VERSION 5.7 ;
  NOWIREEXTENSIONATPIN ON ;
  DIVIDERCHAR "/" ;
  BUSBITCHARS "[]" ;
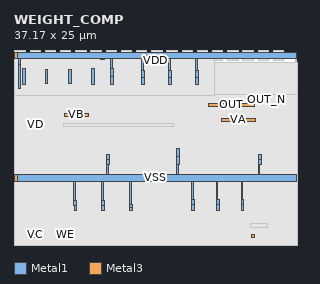
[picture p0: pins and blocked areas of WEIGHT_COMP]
MACRO WEIGHT_COMP
  CLASS BLOCK ;
  FOREIGN WEIGHT_COMP ;
  ORIGIN 1.450 4.210 ;
  SIZE 37.170 BY 25.000 ;
  PIN VSS
    DIRECTION INOUT ;
    USE GROUND ;
    PORT
      LAYER Metal1 ;
        RECT 10.760 6.660 11.120 7.280 ;
        RECT 19.980 7.040 20.340 8.040 ;
        RECT 10.730 6.040 11.120 6.660 ;
        RECT 19.950 6.040 20.340 7.040 ;
        RECT 30.700 6.660 31.060 7.280 ;
        RECT 30.670 6.040 31.060 6.660 ;
        RECT 10.730 4.710 10.960 6.040 ;
        RECT 19.950 4.710 20.180 6.040 ;
        RECT 30.670 4.710 30.900 6.040 ;
        RECT -1.000 3.810 35.720 4.710 ;
        RECT 6.420 1.240 6.650 3.810 ;
        RECT 10.080 1.240 10.310 3.810 ;
        RECT 6.420 0.620 6.810 1.240 ;
        RECT 10.080 0.620 10.470 1.240 ;
        RECT 6.450 0.000 6.810 0.620 ;
        RECT 10.110 0.000 10.470 0.620 ;
        RECT 13.740 0.700 13.970 3.810 ;
        RECT 21.900 1.320 22.130 3.810 ;
        RECT 25.160 1.320 25.390 3.810 ;
        RECT 28.420 1.320 28.650 3.810 ;
        RECT 13.740 0.350 14.130 0.700 ;
        RECT 21.900 0.660 22.290 1.320 ;
        RECT 25.160 0.660 25.550 1.320 ;
        RECT 28.420 0.660 28.810 1.320 ;
        RECT 13.770 0.000 14.130 0.350 ;
        RECT 21.930 0.000 22.290 0.660 ;
        RECT 25.190 0.000 25.550 0.660 ;
        RECT 28.450 0.000 28.810 0.660 ;
      LAYER Metal3 ;
        RECT -1.450 3.810 35.720 4.710 ;
    END
  END VSS
  PIN VDD
    DIRECTION INOUT ;
    USE POWER ;
    PORT
      LAYER Metal1 ;
        RECT -1.000 19.890 35.720 20.790 ;
        RECT -0.865 19.140 -0.635 19.890 ;
        RECT 9.960 19.790 10.440 19.890 ;
        RECT -0.900 15.980 -0.600 19.140 ;
        RECT 11.280 18.560 11.510 19.890 ;
        RECT -0.350 16.560 0.010 18.560 ;
        RECT 2.710 16.580 3.010 18.540 ;
        RECT 5.750 16.580 6.050 18.540 ;
        RECT 8.750 16.560 9.110 18.560 ;
        RECT 11.280 17.560 11.670 18.560 ;
        RECT 11.310 16.560 11.670 17.560 ;
        RECT 15.340 18.390 15.570 19.890 ;
        RECT 17.580 19.790 18.060 19.890 ;
        RECT 18.900 18.390 19.130 19.890 ;
        RECT 22.460 18.390 22.690 19.890 ;
        RECT 15.340 17.475 15.730 18.390 ;
        RECT 18.900 17.475 19.290 18.390 ;
        RECT 22.460 17.475 22.850 18.390 ;
        RECT 15.370 16.560 15.730 17.475 ;
        RECT 18.930 16.560 19.290 17.475 ;
        RECT 22.490 16.560 22.850 17.475 ;
      LAYER Metal3 ;
        RECT -1.450 19.890 35.720 20.790 ;
    END
  END VDD
  PIN VD
    DIRECTION INPUT ;
    ANTENNAGATEAREA 4.960000 ;
    PORT
      LAYER Metal3 ;
      RECT 1.200 11.020 1.600 11.420 ;
    END
  END VD
  PIN WE
    DIRECTION INOUT ;
    ANTENNAGATEAREA 21.706999 ;
    ANTENNADIFFAREA 9.318399 ;
    PORT
      LAYER Metal3 ;
      RECT 5.120 -3.560 5.520 -3.160 ;
    END
  END WE
  PIN VA
    DIRECTION INPUT ;
    ANTENNAGATEAREA 4.960000 ;
    PORT
      LAYER Metal3 ;
      RECT 25.830 11.680 30.330 12.080 ;
    END
  END VA
  PIN VB
    DIRECTION INPUT ;
    ANTENNAGATEAREA 4.960000 ;
    PORT
      LAYER Metal3 ;
      RECT 5.190 12.340 8.290 12.740 ;
    END
  END VB
  PIN OUT
    DIRECTION INOUT ;
    ANTENNAGATEAREA 1.707000 ;
    ANTENNADIFFAREA 1.386000 ;
    PORT
      LAYER Metal3 ;
      RECT 24.105 13.660 30.165 14.060 ;
      RECT 29.765 -3.560 30.165 -3.160 ;
    END
  END OUT
  PIN OUT_N
    DIRECTION INOUT ;
    ANTENNADIFFAREA 1.386000 ;
    PORT
      LAYER Metal3 ;
      RECT 31.565 14.320 31.965 14.720 ;
    END
  END OUT_N
  PIN VC
    DIRECTION INPUT ;
    ANTENNAGATEAREA 4.960000 ;
    PORT
      LAYER Metal3 ;
      RECT 1.200 -3.560 1.600 -3.160 ;
    END
  END VC
  OBS
      LAYER Via1 ;
        RECT 13.970 0.690 15.430 1.510 ;
        RECT 15.470 0.690 16.930 1.510 ;
        RECT 16.970 0.690 18.430 1.510 ;
        RECT -1.340 3.570 0.040 4.950 ;
        RECT 0.660 3.570 2.040 4.950 ;
        RECT 2.660 3.570 4.040 4.950 ;
        RECT 4.660 3.570 6.040 4.950 ;
        RECT 6.660 3.570 8.040 4.950 ;
        RECT 12.660 3.570 14.040 4.950 ;
        RECT 14.660 3.570 16.040 4.950 ;
        RECT 16.660 3.570 18.040 4.950 ;
        RECT 18.660 3.570 20.040 4.950 ;
        RECT 24.660 3.570 26.040 4.950 ;
        RECT 26.660 3.570 28.040 4.950 ;
        RECT -1.440 -4.700 35.875 19.370 ;
        RECT -1.340 19.650 0.040 21.030 ;
        RECT 0.660 19.650 2.040 21.030 ;
        RECT 2.660 19.650 4.040 21.030 ;
        RECT 4.660 19.650 6.040 21.030 ;
        RECT 6.660 19.650 8.040 21.030 ;
        RECT 8.660 19.650 10.040 21.030 ;
        RECT 10.660 19.650 12.040 21.030 ;
        RECT 12.660 19.650 14.040 21.030 ;
        RECT 14.660 19.650 16.040 21.030 ;
        RECT 16.660 19.650 18.040 21.030 ;
        RECT 18.660 19.650 20.040 21.030 ;
        RECT 20.660 19.650 22.040 21.030 ;
        RECT 22.660 19.650 24.040 21.030 ;
        RECT 24.660 19.650 26.040 21.030 ;
        RECT 26.660 19.650 28.040 21.030 ;
        RECT 28.660 19.650 30.040 21.030 ;
        RECT 30.660 19.650 32.040 21.030 ;
        RECT 32.660 19.650 34.040 21.030 ;
      LAYER Via2 ;
        RECT -1.440 -0.410 3.520 0.910 ;
        RECT 0.650 1.570 4.100 2.890 ;
        RECT -1.340 3.570 0.040 4.950 ;
        RECT 0.660 3.570 2.040 4.950 ;
        RECT 2.660 3.570 4.040 4.950 ;
        RECT 4.660 3.570 6.040 4.950 ;
        RECT 6.660 3.570 8.040 4.950 ;
        RECT 12.660 3.570 14.040 4.950 ;
        RECT 14.660 3.570 16.040 4.950 ;
        RECT 16.660 3.570 18.040 4.950 ;
        RECT 18.660 3.570 20.040 4.950 ;
        RECT 24.660 3.570 26.040 4.950 ;
        RECT 26.660 3.570 28.040 4.950 ;
        RECT -1.440 5.630 3.520 6.950 ;
        RECT 4.120 5.630 9.080 6.950 ;
        RECT 13.340 5.630 18.300 6.950 ;
        RECT 24.060 5.630 29.020 6.950 ;
        RECT 15.430 7.130 18.880 8.450 ;
        RECT 0.650 7.610 4.100 8.930 ;
        RECT 26.150 7.610 29.600 8.930 ;
        RECT -1.440 -4.700 35.875 15.210 ;
        RECT -1.430 16.150 9.610 17.470 ;
        RECT 0.660 17.650 10.190 18.970 ;
        RECT -1.340 19.650 0.040 21.030 ;
        RECT 0.660 19.650 2.040 21.030 ;
        RECT 2.660 19.650 4.040 21.030 ;
        RECT 4.660 19.650 6.040 21.030 ;
        RECT 6.660 19.650 8.040 21.030 ;
        RECT 8.660 19.650 10.040 21.030 ;
        RECT 10.660 19.650 12.040 21.030 ;
        RECT 12.660 19.650 14.040 21.030 ;
        RECT 14.660 19.650 16.040 21.030 ;
        RECT 16.660 19.650 18.040 21.030 ;
        RECT 18.660 19.650 20.040 21.030 ;
        RECT 20.660 19.650 22.040 21.030 ;
        RECT 22.660 19.650 24.040 21.030 ;
        RECT 24.660 19.650 26.040 21.030 ;
        RECT 26.660 19.650 28.040 21.030 ;
        RECT 28.660 19.650 30.040 21.030 ;
        RECT 30.660 19.650 32.040 21.030 ;
        RECT 32.660 19.650 34.040 21.030 ;
      LAYER Via3 ;
        RECT 29.710 -2.240 31.965 -1.840 ;
        RECT 5.120 11.020 19.520 11.420 ;
        RECT 30.665 14.320 31.065 14.720 ;
      LAYER Metal1 ;
        RECT 21.240 -4.420 22.080 -0.980 ;
        RECT 32.850 -4.420 33.690 -0.980 ;
        RECT 33.810 -3.760 34.650 -0.980 ;
        RECT 34.775 -2.440 35.615 -0.980 ;
        RECT 13.970 -3.100 15.430 0.010 ;
        RECT 15.470 -3.100 16.930 0.010 ;
        RECT 16.970 -3.100 18.430 0.010 ;
        RECT 13.970 0.690 15.430 1.510 ;
        RECT 15.470 0.690 16.930 1.510 ;
        RECT 16.970 0.690 18.430 1.510 ;
        RECT 18.470 -3.100 20.445 1.510 ;
        RECT 6.650 -4.420 8.625 2.050 ;
        RECT 9.900 -4.420 12.285 2.050 ;
        RECT 22.130 -4.420 23.705 2.130 ;
        RECT 25.390 -4.420 26.965 2.130 ;
        RECT 28.650 -3.760 31.020 2.130 ;
        RECT -1.160 -4.420 3.820 3.290 ;
        RECT 20.180 5.230 21.640 6.050 ;
        RECT 20.180 5.230 23.655 12.280 ;
        RECT 24.340 5.230 29.320 12.280 ;
        RECT 30.180 9.500 31.020 12.940 ;
        RECT 30.900 5.230 33.690 13.600 ;
        RECT 33.810 9.500 34.650 14.260 ;
        RECT 34.775 9.500 35.615 14.920 ;
        RECT 13.620 5.230 18.600 19.200 ;
        RECT 19.130 12.800 20.605 19.200 ;
        RECT 22.690 13.460 24.165 19.200 ;
        RECT -1.160 5.230 10.740 19.370 ;
        RECT 10.960 5.230 13.485 19.370 ;
      LAYER Metal2 ;
        RECT -1.440 -0.410 3.520 0.910 ;
        RECT 0.650 1.570 4.100 2.890 ;
        RECT -1.340 3.570 0.040 4.950 ;
        RECT 0.660 3.570 2.040 4.950 ;
        RECT 2.660 3.570 4.040 4.950 ;
        RECT 4.660 3.570 6.040 4.950 ;
        RECT 6.660 3.570 8.040 4.950 ;
        RECT 12.660 3.570 14.040 4.950 ;
        RECT 14.660 3.570 16.040 4.950 ;
        RECT 16.660 3.570 18.040 4.950 ;
        RECT 18.660 3.570 20.040 4.950 ;
        RECT 24.660 3.570 26.040 4.950 ;
        RECT 26.660 3.570 28.040 4.950 ;
        RECT -1.440 5.630 3.520 6.950 ;
        RECT 4.120 5.630 9.080 6.950 ;
        RECT 13.340 5.630 18.300 6.950 ;
        RECT 24.060 5.630 29.020 6.950 ;
        RECT 15.430 7.130 18.880 8.450 ;
        RECT 0.650 7.610 4.100 8.930 ;
        RECT 26.150 7.610 29.600 8.930 ;
        RECT -1.440 -4.700 35.875 15.210 ;
        RECT -1.430 16.150 9.610 17.470 ;
        RECT 0.660 17.650 10.190 18.970 ;
        RECT -1.340 19.650 0.040 21.030 ;
        RECT 0.660 19.650 2.040 21.030 ;
        RECT 2.660 19.650 4.040 21.030 ;
        RECT 4.660 19.650 6.040 21.030 ;
        RECT 6.660 19.650 8.040 21.030 ;
        RECT 8.660 19.650 10.040 21.030 ;
        RECT 10.660 19.650 12.040 21.030 ;
        RECT 12.660 19.650 14.040 21.030 ;
        RECT 14.660 19.650 16.040 21.030 ;
        RECT 16.660 19.650 18.040 21.030 ;
        RECT 18.660 19.650 20.040 21.030 ;
        RECT 20.660 19.650 22.040 21.030 ;
        RECT 22.660 19.650 24.040 21.030 ;
        RECT 24.660 19.650 26.040 21.030 ;
        RECT 26.660 19.650 28.040 21.030 ;
        RECT 28.660 19.650 30.040 21.030 ;
        RECT 30.660 19.650 32.040 21.030 ;
        RECT 32.660 19.650 34.040 21.030 ;
      LAYER Metal3 ;
        RECT 29.710 -2.240 31.965 -1.840 ;
        RECT 5.120 11.020 19.520 11.420 ;
        RECT 30.665 14.320 31.065 14.720 ;
      LAYER Nwell ;
        RECT -1.450 15.080 24.950 20.790 ;
  END
END WEIGHT_COMP
